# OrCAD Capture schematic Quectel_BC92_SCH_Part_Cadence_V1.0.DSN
size A2

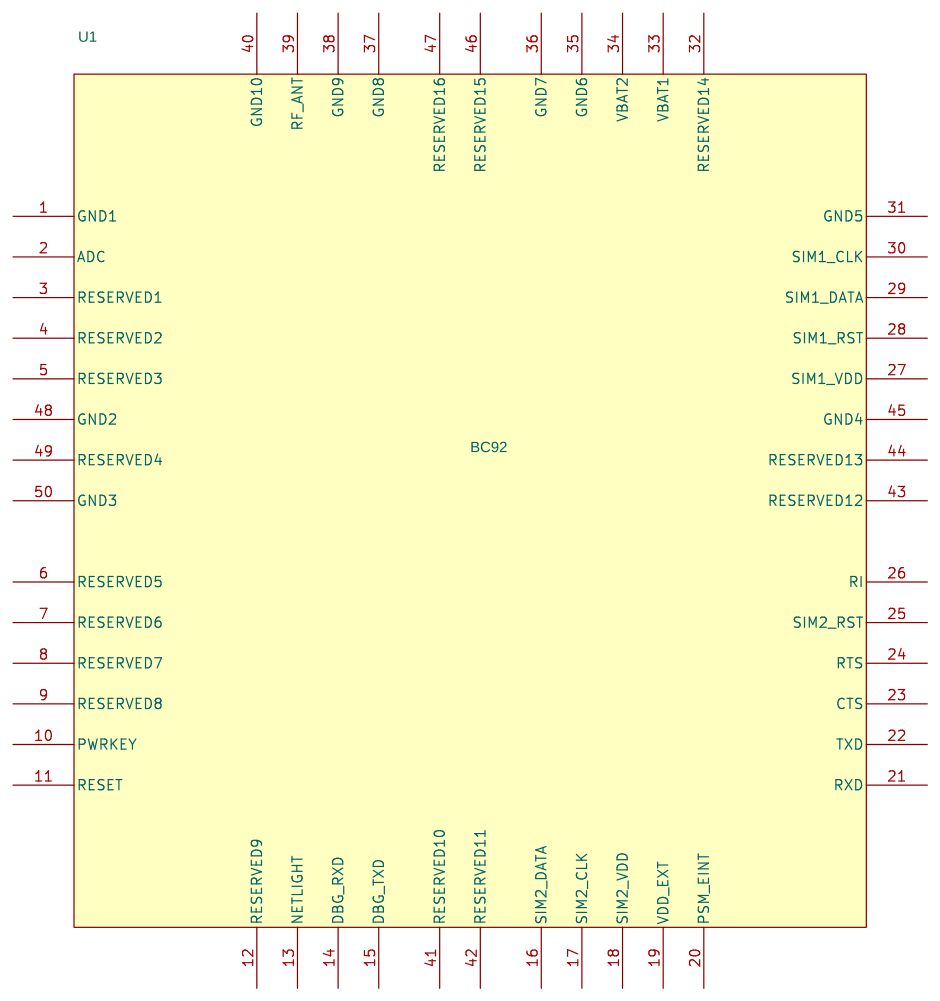
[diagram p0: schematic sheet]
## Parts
U1  BC92  [BC92]

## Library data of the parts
U1 = BC92

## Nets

Not connected (* = marked no-connect by the designer): U1 1(GND1) 2(ADC) 3(RESERVED1) 4(RESERVED2) 5(RESERVED3) 6(RESERVED5) 7(RESERVED6) 8(RESERVED7) 9(RESERVED8) 10(PWRKEY) 11(RESET) 12(RESERVED9) 13(NETLIGHT) 14(DBG_RXD) 15(DBG_TXD) 16(SIM2_DATA) 17(SIM2_CLK) 18(SIM2_VDD) 19(VDD_EXT) 20(PSM_EINT) 21(RXD) 22(TXD) 23(CTS) 24(RTS) 25(SIM2_RST) 26(RI) 27(SIM1_VDD) 28(SIM1_RST) 29(SIM1_DATA) 30(SIM1_CLK) 31(GND5) 32(RESERVED14) 33(VBAT1) 34(VBAT2) 35(GND6) 36(GND7) 37(GND8) 38(GND9) 39(RF_ANT) 40(GND10) 41(RESERVED10) 42(RESERVED11) 43(RESERVED12) 44(RESERVED13) 45(GND4) 46(RESERVED15) 47(RESERVED16) 48(GND2) 49(RESERVED4) 50(GND3)
